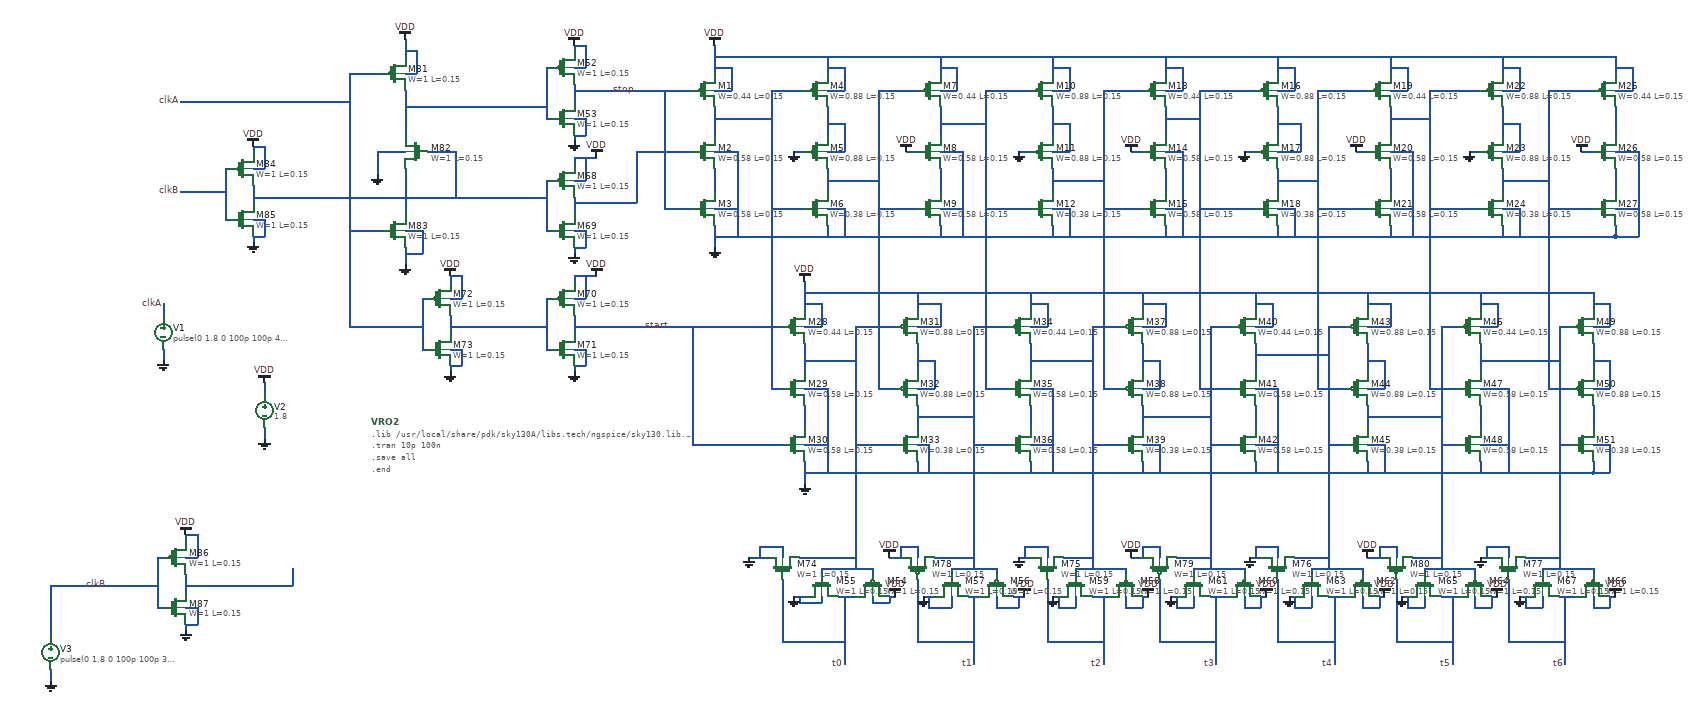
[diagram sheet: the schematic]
v {xschem version=3.4.6 file_version=1.2}
G {}
K {}
V {}
S {}
E {}
N -170 -50 -170 -20 {lab=stop}
N -170 -120 -170 -110 {lab=VDD}
N -170 40 -170 50 {lab=GND}
N -220 -80 -210 -80 {lab=#net1}
N -220 -80 -220 10 {lab=#net1}
N -220 10 -200 10 {lab=#net1}
N 300 860 330 860 {lab=t0}
N 390 860 400 860 {lab=VDD}
N 360 810 360 820 {lab=#net2}
N 270 810 360 810 {lab=#net2}
N 270 810 270 830 {lab=#net2}
N 750 860 780 860 {lab=t2}
N 840 860 850 860 {lab=VDD}
N 680 860 690 860 {lab=GND}
N 810 810 810 820 {lab=#net3}
N 720 810 810 810 {lab=#net3}
N 720 810 720 830 {lab=#net3}
N 960 860 990 860 {lab=t3}
N 1050 860 1060 860 {lab=VDD}
N 890 860 900 860 {lab=GND}
N 1020 810 1020 820 {lab=#net4}
N 930 810 1020 810 {lab=#net4}
N 930 810 930 830 {lab=#net4}
N 1170 860 1200 860 {lab=t4}
N 1260 860 1270 860 {lab=VDD}
N 1100 860 1110 860 {lab=GND}
N 1230 810 1230 820 {lab=#net5}
N 1140 810 1230 810 {lab=#net5}
N 1140 810 1140 830 {lab=#net5}
N 1370 860 1400 860 {lab=t5}
N 1460 860 1470 860 {lab=VDD}
N 1430 810 1430 820 {lab=#net6}
N 1340 810 1430 810 {lab=#net6}
N 1340 810 1340 830 {lab=#net6}
N 1580 860 1610 860 {lab=t6}
N 1670 860 1680 860 {lab=VDD}
N 1510 860 1520 860 {lab=GND}
N 1640 810 1640 820 {lab=#net7}
N 1550 810 1640 810 {lab=#net7}
N 1550 810 1550 830 {lab=#net7}
N -170 150 -170 180 {lab=#net8}
N -170 240 -170 250 {lab=GND}
N -220 120 -210 120 {lab=#net9}
N -220 120 -220 210 {lab=#net9}
N -220 210 -200 210 {lab=#net9}
N -170 360 -170 390 {lab=start}
N -170 450 -170 460 {lab=GND}
N -220 330 -210 330 {lab=#net10}
N -220 330 -220 420 {lab=#net10}
N -220 420 -200 420 {lab=#net10}
N -390 360 -390 390 {lab=#net10}
N -390 290 -390 300 {lab=VDD}
N -390 450 -390 460 {lab=GND}
N -440 330 -430 330 {lab=clkA}
N -440 330 -440 420 {lab=clkA}
N -440 420 -420 420 {lab=clkA}
N -740 130 -740 160 {lab=#net9}
N -740 60 -740 70 {lab=VDD}
N -740 220 -740 230 {lab=GND}
N -790 100 -780 100 {lab=clkB}
N -790 100 -790 190 {lab=clkB}
N -790 190 -770 190 {lab=clkB}
N -170 -40 40 -40 {lab=stop}
N -60 70 40 70 {lab=#net8}
N -60 70 -60 160 {lab=#net8}
N -170 160 -60 160 {lab=#net8}
N -10 170 40 170 {lab=stop}
N -10 -40 -10 170 {lab=stop}
N 80 -120 80 -70 {lab=VDD}
N 80 -10 80 40 {lab=#net11}
N 80 100 80 140 {lab=#net12}
N 80 200 80 240 {lab=GND}
N 280 -100 280 -70 {lab=VDD}
N 280 -10 280 40 {lab=#net13}
N 280 100 280 150 {lab=#net14}
N 280 200 280 220 {lab=GND}
N 480 -100 480 -70 {lab=VDD}
N 480 -10 480 40 {lab=#net15}
N 480 100 480 140 {lab=#net16}
N 480 200 480 220 {lab=GND}
N 680 -100 680 -70 {lab=VDD}
N 680 -10 680 40 {lab=#net17}
N 680 100 680 140 {lab=#net18}
N 680 200 680 220 {lab=GND}
N 880 -100 880 -70 {lab=VDD}
N 880 -10 880 40 {lab=#net19}
N 880 100 880 140 {lab=#net20}
N 880 200 880 220 {lab=GND}
N 1080 -100 1080 -70 {lab=VDD}
N 1080 -10 1080 40 {lab=#net21}
N 1080 100 1080 140 {lab=#net22}
N 1080 200 1080 220 {lab=GND}
N 1280 -100 1280 -70 {lab=VDD}
N 1280 -10 1280 40 {lab=#net23}
N 1280 100 1280 140 {lab=#net24}
N 1280 200 1280 220 {lab=GND}
N 1480 -100 1480 -70 {lab=VDD}
N 1480 -10 1480 40 {lab=#net25}
N 1480 100 1480 140 {lab=#net26}
N 1480 200 1480 220 {lab=GND}
N 1680 -100 1680 -70 {lab=VDD}
N 1680 -10 1680 50 {lab=#net27}
N 1680 100 1680 140 {lab=#net28}
N 1680 200 1680 220 {lab=GND}
N 80 -100 1680 -100 {lab=VDD}
N 80 220 1680 220 {lab=GND}
N -170 380 200 380 {lab=start}
N 40 590 200 590 {lab=start}
N 40 380 40 590 {lab=start}
N 240 300 240 350 {lab=VDD}
N 240 410 240 460 {lab=#net2}
N 240 520 240 560 {lab=#net29}
N 240 620 240 660 {lab=GND}
N 440 320 440 350 {lab=VDD}
N 440 410 440 460 {lab=#net30}
N 440 520 440 570 {lab=#net31}
N 440 620 440 640 {lab=GND}
N 640 320 640 350 {lab=VDD}
N 640 410 640 460 {lab=#net3}
N 640 520 640 560 {lab=#net32}
N 640 620 640 640 {lab=GND}
N 840 320 840 350 {lab=VDD}
N 840 410 840 470 {lab=#net33}
N 840 520 840 560 {lab=#net4}
N 840 620 840 640 {lab=GND}
N 1040 320 1040 350 {lab=VDD}
N 1040 410 1040 460 {lab=#net5}
N 1040 520 1040 570 {lab=#net34}
N 1040 620 1040 640 {lab=GND}
N 1240 320 1240 350 {lab=VDD}
N 1240 410 1240 460 {lab=#net35}
N 1240 520 1240 560 {lab=#net6}
N 1240 620 1240 640 {lab=GND}
N 1440 320 1440 350 {lab=VDD}
N 1440 410 1440 470 {lab=#net7}
N 1440 520 1440 560 {lab=#net36}
N 1440 620 1440 640 {lab=GND}
N 1640 320 1640 350 {lab=VDD}
N 1640 410 1640 470 {lab=#net37}
N 1640 520 1640 570 {lab=#net38}
N 1640 620 1640 640 {lab=GND}
N 240 320 1640 320 {lab=VDD}
N 240 640 1640 640 {lab=GND}
N 180 -40 240 -40 {lab=#net11}
N 180 -40 180 490 {lab=#net11}
N 180 490 200 490 {lab=#net11}
N 370 -40 440 -40 {lab=#net14}
N 370 -40 370 490 {lab=#net14}
N 370 490 400 490 {lab=#net14}
N 560 -40 640 -40 {lab=#net15}
N 560 -40 560 490 {lab=#net15}
N 560 490 600 490 {lab=#net15}
N 940 -40 1040 -40 {lab=#net19}
N 940 -40 940 490 {lab=#net19}
N 940 490 1010 490 {lab=#net19}
N 1150 -40 1240 -40 {lab=#net22}
N 1150 -40 1150 490 {lab=#net22}
N 1150 490 1200 490 {lab=#net22}
N 1350 -40 1440 -40 {lab=#net23}
N 1350 -40 1350 490 {lab=#net23}
N 1350 490 1400 490 {lab=#net23}
N 1560 -40 1640 -40 {lab=#net26}
N 1560 -40 1560 490 {lab=#net26}
N 1560 490 1610 490 {lab=#net26}
N 80 10 180 10 {lab=#net11}
N 180 170 240 170 {lab=#net11}
N 280 120 370 120 {lab=#net14}
N 370 170 440 170 {lab=#net14}
N 480 20 560 20 {lab=#net15}
N 560 170 640 170 {lab=#net15}
N 770 -40 840 -40 {lab=#net18}
N 770 -40 770 490 {lab=#net18}
N 770 490 800 490 {lab=#net18}
N 680 120 770 120 {lab=#net18}
N 770 170 840 170 {lab=#net18}
N 880 10 940 10 {lab=#net19}
N 940 170 1040 170 {lab=#net19}
N 1080 120 1150 120 {lab=#net22}
N 1150 170 1240 170 {lab=#net22}
N 1280 10 1350 10 {lab=#net23}
N 1350 170 1440 170 {lab=#net23}
N 1480 120 1560 120 {lab=#net26}
N 1560 170 1640 170 {lab=#net26}
N 80 -40 110 -40 {lab=VDD}
N 110 -80 110 -40 {lab=VDD}
N 80 -80 110 -80 {lab=VDD}
N 80 70 120 70 {lab=GND}
N 120 70 120 220 {lab=GND}
N 80 170 120 170 {lab=GND}
N 280 -40 310 -40 {lab=VDD}
N 310 -80 310 -40 {lab=VDD}
N 280 -80 310 -80 {lab=VDD}
N 280 70 310 70 {lab=#net13}
N 310 20 310 70 {lab=#net13}
N 280 20 310 20 {lab=#net13}
N 280 170 310 170 {lab=GND}
N 310 170 310 220 {lab=GND}
N 480 -40 510 -40 {lab=VDD}
N 510 -80 510 -40 {lab=VDD}
N 480 -80 510 -80 {lab=VDD}
N 480 70 520 70 {lab=GND}
N 520 70 520 220 {lab=GND}
N 480 170 520 170 {lab=GND}
N 680 -40 710 -40 {lab=VDD}
N 710 -80 710 -40 {lab=VDD}
N 680 -80 710 -80 {lab=VDD}
N 680 70 710 70 {lab=#net17}
N 710 20 710 70 {lab=#net17}
N 680 20 710 20 {lab=#net17}
N 680 170 710 170 {lab=GND}
N 710 170 710 220 {lab=GND}
N 880 -40 910 -40 {lab=VDD}
N 910 -80 910 -40 {lab=VDD}
N 880 -80 910 -80 {lab=VDD}
N 880 70 910 70 {lab=GND}
N 910 70 910 220 {lab=GND}
N 880 170 910 170 {lab=GND}
N 1080 -40 1110 -40 {lab=VDD}
N 1110 -80 1110 -40 {lab=VDD}
N 1080 -80 1110 -80 {lab=VDD}
N 1080 70 1120 70 {lab=#net21}
N 1120 20 1120 70 {lab=#net21}
N 1080 20 1120 20 {lab=#net21}
N 1080 170 1110 170 {lab=GND}
N 1110 170 1110 220 {lab=GND}
N 1280 -40 1310 -40 {lab=VDD}
N 1310 -80 1310 -40 {lab=VDD}
N 1280 -80 1310 -80 {lab=VDD}
N 1280 70 1320 70 {lab=GND}
N 1320 70 1320 220 {lab=GND}
N 1280 170 1320 170 {lab=GND}
N 1480 -40 1510 -40 {lab=VDD}
N 1510 -80 1510 -40 {lab=VDD}
N 1480 -80 1510 -80 {lab=VDD}
N 1480 70 1510 70 {lab=#net25}
N 1510 20 1510 70 {lab=#net25}
N 1480 20 1510 20 {lab=#net25}
N 1480 170 1510 170 {lab=GND}
N 1510 170 1510 220 {lab=GND}
N 1680 -40 1710 -40 {lab=VDD}
N 1710 -80 1710 -40 {lab=VDD}
N 1680 -80 1710 -80 {lab=VDD}
N 1680 70 1720 70 {lab=GND}
N 1720 70 1720 220 {lab=GND}
N 1680 220 1720 220 {lab=GND}
N 1680 170 1720 170 {lab=GND}
N 220 70 240 70 {lab=GND}
N 420 70 440 70 {lab=VDD}
N 620 70 640 70 {lab=GND}
N 820 70 840 70 {lab=VDD}
N 1020 70 1040 70 {lab=GND}
N 1220 70 1240 70 {lab=VDD}
N 1420 70 1440 70 {lab=GND}
N 1620 70 1640 70 {lab=VDD}
N 330 380 400 380 {lab=#net2}
N 330 380 330 810 {lab=#net2}
N 240 440 330 440 {lab=#net2}
N 330 590 400 590 {lab=#net2}
N 750 380 800 380 {lab=#net3}
N 750 380 750 810 {lab=#net3}
N 640 440 750 440 {lab=#net3}
N 750 590 800 590 {lab=#net3}
N 540 380 600 380 {lab=#net31}
N 540 380 540 810 {lab=#net31}
N 440 540 540 540 {lab=#net31}
N 540 590 600 590 {lab=#net31}
N 960 380 1000 380 {lab=#net4}
N 960 380 960 810 {lab=#net4}
N 840 540 960 540 {lab=#net4}
N 960 590 1000 590 {lab=#net4}
N 1170 380 1200 380 {lab=#net5}
N 1170 380 1170 810 {lab=#net5}
N 1040 430 1170 430 {lab=#net5}
N 1170 590 1200 590 {lab=#net5}
N 1370 380 1400 380 {lab=#net6}
N 1370 380 1370 810 {lab=#net6}
N 1370 590 1400 590 {lab=#net6}
N 1240 540 1370 540 {lab=#net6}
N 1580 380 1600 380 {lab=#net7}
N 1580 380 1580 810 {lab=#net7}
N 1440 440 1580 440 {lab=#net7}
N 1580 590 1600 590 {lab=#net7}
N 1640 590 1670 590 {lab=GND}
N 1670 590 1670 640 {lab=GND}
N 1640 640 1670 640 {lab=GND}
N 1640 380 1670 380 {lab=VDD}
N 1670 340 1670 380 {lab=VDD}
N 1640 340 1670 340 {lab=VDD}
N 1640 490 1670 490 {lab=#net37}
N 1670 440 1670 490 {lab=#net37}
N 1640 440 1670 440 {lab=#net37}
N 1440 380 1470 380 {lab=VDD}
N 1470 340 1470 380 {lab=VDD}
N 1440 340 1470 340 {lab=VDD}
N 1440 490 1490 490 {lab=GND}
N 1490 490 1490 640 {lab=GND}
N 1440 590 1490 590 {lab=GND}
N 1240 380 1280 380 {lab=VDD}
N 1280 340 1280 380 {lab=VDD}
N 1240 340 1280 340 {lab=VDD}
N 1240 490 1270 490 {lab=#net35}
N 1270 440 1270 490 {lab=#net35}
N 1240 440 1270 440 {lab=#net35}
N 1240 590 1270 590 {lab=GND}
N 1270 590 1270 640 {lab=GND}
N 1040 380 1070 380 {lab=VDD}
N 1070 340 1070 380 {lab=VDD}
N 1040 340 1070 340 {lab=VDD}
N 1040 490 1080 490 {lab=GND}
N 1080 490 1080 640 {lab=GND}
N 1040 590 1080 590 {lab=GND}
N 840 380 880 380 {lab=VDD}
N 880 340 880 380 {lab=VDD}
N 840 340 880 340 {lab=VDD}
N 840 490 870 490 {lab=#net33}
N 870 440 870 490 {lab=#net33}
N 840 440 870 440 {lab=#net33}
N 840 590 870 590 {lab=GND}
N 870 590 870 640 {lab=GND}
N 640 380 670 380 {lab=VDD}
N 670 340 670 380 {lab=VDD}
N 640 340 670 340 {lab=VDD}
N 640 490 680 490 {lab=GND}
N 680 490 680 640 {lab=GND}
N 640 590 680 590 {lab=GND}
N 440 380 480 380 {lab=VDD}
N 480 340 480 380 {lab=VDD}
N 440 340 480 340 {lab=VDD}
N 440 490 470 490 {lab=#net30}
N 470 440 470 490 {lab=#net30}
N 440 440 470 440 {lab=#net30}
N 440 590 460 590 {lab=GND}
N 460 590 460 640 {lab=GND}
N 240 380 270 380 {lab=VDD}
N 270 340 270 380 {lab=VDD}
N 240 340 270 340 {lab=VDD}
N 240 490 280 490 {lab=GND}
N 280 490 280 640 {lab=GND}
N 240 590 280 590 {lab=GND}
N 230 790 330 790 {lab=#net2}
N 470 790 540 790 {lab=#net31}
N 700 790 750 790 {lab=#net3}
N 900 790 960 790 {lab=#net4}
N 1110 790 1170 790 {lab=#net5}
N 1320 790 1370 790 {lab=#net6}
N 1520 790 1580 790 {lab=#net7}
N 140 790 170 790 {lab=GND}
N 390 790 410 790 {lab=VDD}
N 620 790 640 790 {lab=GND}
N 820 790 840 790 {lab=VDD}
N 1030 790 1050 790 {lab=GND}
N 1240 790 1260 790 {lab=VDD}
N 1440 790 1460 790 {lab=GND}
N 1300 860 1310 860 {lab=GND}
N 310 860 310 980 {lab=t0}
N 540 860 540 980 {lab=t1}
N 770 860 770 980 {lab=t2}
N 970 860 970 980 {lab=t3}
N 1180 860 1180 980 {lab=t4}
N 1390 860 1390 980 {lab=t5}
N 1590 860 1590 980 {lab=t6}
N 200 830 200 940 {lab=t0}
N 200 940 310 940 {lab=t0}
N 440 830 440 940 {lab=t1}
N 440 940 540 940 {lab=t1}
N 670 830 670 940 {lab=t2}
N 670 940 770 940 {lab=t2}
N 870 830 870 940 {lab=t3}
N 870 940 970 940 {lab=t3}
N 1080 830 1080 940 {lab=t4}
N 1080 940 1180 940 {lab=t4}
N 1290 830 1290 940 {lab=t5}
N 1290 940 1390 940 {lab=t5}
N 1490 830 1490 940 {lab=t6}
N 1490 940 1590 940 {lab=t6}
N -570 -70 -510 -70 {lab=clkA}
N -570 -70 -570 380 {lab=clkA}
N -570 380 -440 380 {lab=clkA}
N -570 210 -510 210 {lab=clkA}
N -470 240 -470 270 {lab=GND}
N -470 210 -440 210 {lab=GND}
N -440 210 -440 250 {lab=GND}
N -470 250 -440 250 {lab=GND}
N -470 100 -470 180 {lab=#net39}
N -520 70 -470 70 {lab=GND}
N -520 70 -520 110 {lab=GND}
N -740 150 -220 150 {lab=#net9}
N -430 70 -380 70 {lab=#net9}
N -380 70 -380 150 {lab=#net9}
N -470 -40 -470 40 {lab=#net1}
N -470 -10 -220 -10 {lab=#net1}
N -390 380 -220 380 {lab=#net10}
N -470 -130 -470 -100 {lab=VDD}
N -470 -70 -450 -70 {lab=VDD}
N -450 -110 -450 -70 {lab=VDD}
N -470 -110 -450 -110 {lab=VDD}
N 270 860 270 870 {lab=GND}
N 230 870 270 870 {lab=GND}
N 230 860 230 870 {lab=GND}
N 220 860 240 860 {lab=GND}
N 360 860 360 870 {lab=VDD}
N 360 870 390 870 {lab=VDD}
N 390 860 390 870 {lab=VDD}
N 720 860 720 880 {lab=GND}
N 690 880 720 880 {lab=GND}
N 690 860 690 880 {lab=GND}
N 810 860 810 880 {lab=VDD}
N 810 880 840 880 {lab=VDD}
N 840 860 840 880 {lab=VDD}
N 930 860 930 880 {lab=GND}
N 900 880 930 880 {lab=GND}
N 900 860 900 880 {lab=GND}
N 1020 860 1020 880 {lab=VDD}
N 1020 880 1050 880 {lab=VDD}
N 1050 860 1050 880 {lab=VDD}
N 1140 860 1140 880 {lab=GND}
N 1110 880 1140 880 {lab=GND}
N 1110 860 1110 880 {lab=GND}
N 1230 860 1230 880 {lab=VDD}
N 1230 880 1260 880 {lab=VDD}
N 1260 860 1260 880 {lab=VDD}
N 1340 860 1340 880 {lab=GND}
N 1310 880 1340 880 {lab=GND}
N 1310 860 1310 880 {lab=GND}
N 1430 860 1430 880 {lab=VDD}
N 1430 880 1460 880 {lab=VDD}
N 1460 860 1460 880 {lab=VDD}
N 1550 860 1550 880 {lab=GND}
N 1520 880 1550 880 {lab=GND}
N 1520 860 1520 880 {lab=GND}
N 1640 860 1640 880 {lab=VDD}
N 1640 880 1670 880 {lab=VDD}
N 1670 860 1670 880 {lab=VDD}
N -170 -80 -150 -80 {lab=VDD}
N -150 -120 -150 -80 {lab=VDD}
N -170 -120 -150 -120 {lab=VDD}
N -170 10 -150 10 {lab=GND}
N -150 10 -150 40 {lab=GND}
N -170 40 -150 40 {lab=GND}
N -170 80 -170 90 {lab=VDD}
N -170 80 -130 80 {lab=VDD}
N -170 120 -150 120 {lab=VDD}
N -150 80 -150 120 {lab=VDD}
N -170 210 -150 210 {lab=GND}
N -150 210 -150 240 {lab=GND}
N -170 240 -150 240 {lab=GND}
N -170 290 -170 300 {lab=VDD}
N -170 290 -130 290 {lab=VDD}
N -170 330 -150 330 {lab=VDD}
N -150 290 -150 330 {lab=VDD}
N -170 420 -150 420 {lab=GND}
N -150 420 -150 450 {lab=GND}
N -170 450 -150 450 {lab=GND}
N -390 420 -370 420 {lab=GND}
N -370 420 -370 450 {lab=GND}
N -390 450 -370 450 {lab=GND}
N -390 330 -370 330 {lab=VDD}
N -370 290 -370 330 {lab=VDD}
N -390 290 -370 290 {lab=VDD}
N -740 100 -720 100 {lab=VDD}
N -720 60 -720 100 {lab=VDD}
N -740 60 -720 60 {lab=VDD}
N -740 190 -720 190 {lab=GND}
N -720 190 -720 220 {lab=GND}
N -740 220 -720 220 {lab=GND}
N -870 140 -790 140 {lab=clkB}
N -870 -20 -570 -20 {lab=clkA}
N -900 340 -900 360 {lab=clkA}
N -900 420 -900 440 {lab=GND}
N -720 480 -720 500 {lab=VDD}
N -720 560 -720 580 {lab=GND}
N -1100 910 -1100 930 {lab=clkB}
N -1100 990 -1100 1010 {lab=GND}
N 200 770 200 790 {lab=GND}
N 160 770 200 770 {lab=GND}
N 160 770 160 790 {lab=GND}
N 440 770 440 790 {lab=VDD}
N 410 770 440 770 {lab=VDD}
N 410 770 410 790 {lab=VDD}
N 670 770 670 790 {lab=GND}
N 630 770 670 770 {lab=GND}
N 630 770 630 790 {lab=GND}
N 870 770 870 790 {lab=VDD}
N 840 770 870 770 {lab=VDD}
N 840 770 840 790 {lab=VDD}
N 1080 770 1080 790 {lab=GND}
N 1040 770 1080 770 {lab=GND}
N 1040 770 1040 790 {lab=GND}
N 1290 770 1290 790 {lab=VDD}
N 1260 770 1290 770 {lab=VDD}
N 1260 770 1260 790 {lab=VDD}
N 1490 770 1490 790 {lab=GND}
N 1450 770 1490 770 {lab=GND}
N 1450 770 1450 790 {lab=GND}
N 500 810 580 810 {lab=#net31}
N 580 810 580 830 {lab=#net31}
N 610 860 630 860 {lab=VDD}
N 580 860 580 880 {lab=VDD}
N 580 880 620 880 {lab=VDD}
N 620 860 620 880 {lab=VDD}
N 530 860 550 860 {lab=t1}
N 500 810 500 820 {lab=#net31}
N 450 860 470 860 {lab=GND}
N 500 860 500 880 {lab=GND}
N 460 880 500 880 {lab=GND}
N 460 860 460 880 {lab=GND}
N -860 820 -860 850 {lab=#net40}
N -860 750 -860 760 {lab=VDD}
N -860 910 -860 920 {lab=GND}
N -910 790 -900 790 {lab=clkB}
N -910 790 -910 880 {lab=clkB}
N -910 880 -890 880 {lab=clkB}
N -1040 840 -910 840 {lab=clkB}
N -860 840 -690 840 {lab=#net40}
N -860 880 -840 880 {lab=GND}
N -840 880 -840 910 {lab=GND}
N -860 910 -840 910 {lab=GND}
N -860 790 -840 790 {lab=VDD}
N -840 750 -840 790 {lab=VDD}
N -860 750 -840 750 {lab=VDD}
N -1100 840 -1100 910 {lab=clkB}
N -1100 840 -1040 840 {lab=clkB}
N -690 840 -670 840 {lab=#net40}
N -670 810 -670 840 {lab=#net40}
C {/usr/local/share/pdk/sky130A/libs.tech/xschem/sky130_fd_pr/pfet_01v8.sym} 60 -40 0 0 {name=M1
W=0.44
L=0.15
nf=1
mult=1
ad="'int((nf+1)/2) * W/nf * 0.29'" 
pd="'2*int((nf+1)/2) * (W/nf + 0.29)'"
as="'int((nf+2)/2) * W/nf * 0.29'" 
ps="'2*int((nf+2)/2) * (W/nf + 0.29)'"
nrd="'0.29 / W'" nrs="'0.29 / W'"
sa=0 sb=0 sd=0
model=pfet_01v8
spiceprefix=X
}
C {/usr/local/share/pdk/sky130A/libs.tech/xschem/sky130_fd_pr/nfet_01v8.sym} 60 70 0 0 {name=M2
W=0.58
L=0.15
nf=1 
mult=1
ad="'int((nf+1)/2) * W/nf * 0.29'" 
pd="'2*int((nf+1)/2) * (W/nf + 0.29)'"
as="'int((nf+2)/2) * W/nf * 0.29'" 
ps="'2*int((nf+2)/2) * (W/nf + 0.29)'"
nrd="'0.29 / W'" nrs="'0.29 / W'"
sa=0 sb=0 sd=0
model=nfet_01v8
spiceprefix=X
}
C {/usr/local/share/pdk/sky130A/libs.tech/xschem/sky130_fd_pr/nfet_01v8.sym} 60 170 0 0 {name=M3
W=0.58
L=0.15
nf=1 
mult=1
ad="'int((nf+1)/2) * W/nf * 0.29'" 
pd="'2*int((nf+1)/2) * (W/nf + 0.29)'"
as="'int((nf+2)/2) * W/nf * 0.29'" 
ps="'2*int((nf+2)/2) * (W/nf + 0.29)'"
nrd="'0.29 / W'" nrs="'0.29 / W'"
sa=0 sb=0 sd=0
model=nfet_01v8
spiceprefix=X
}
C {/usr/local/share/pdk/sky130A/libs.tech/xschem/sky130_fd_pr/pfet_01v8.sym} 260 -40 0 0 {name=M4
W=0.88
L=0.15
nf=1
mult=1
ad="'int((nf+1)/2) * W/nf * 0.29'" 
pd="'2*int((nf+1)/2) * (W/nf + 0.29)'"
as="'int((nf+2)/2) * W/nf * 0.29'" 
ps="'2*int((nf+2)/2) * (W/nf + 0.29)'"
nrd="'0.29 / W'" nrs="'0.29 / W'"
sa=0 sb=0 sd=0
model=pfet_01v8
spiceprefix=X
}
C {/usr/local/share/pdk/sky130A/libs.tech/xschem/sky130_fd_pr/pfet_01v8.sym} 260 70 0 0 {name=M5
W=0.88
L=0.15
nf=1
mult=1
ad="'int((nf+1)/2) * W/nf * 0.29'" 
pd="'2*int((nf+1)/2) * (W/nf + 0.29)'"
as="'int((nf+2)/2) * W/nf * 0.29'" 
ps="'2*int((nf+2)/2) * (W/nf + 0.29)'"
nrd="'0.29 / W'" nrs="'0.29 / W'"
sa=0 sb=0 sd=0
model=pfet_01v8
spiceprefix=X
}
C {/usr/local/share/pdk/sky130A/libs.tech/xschem/sky130_fd_pr/nfet_01v8.sym} 260 170 0 0 {name=M6
W=0.38
L=0.15
nf=1 
mult=1
ad="'int((nf+1)/2) * W/nf * 0.29'" 
pd="'2*int((nf+1)/2) * (W/nf + 0.29)'"
as="'int((nf+2)/2) * W/nf * 0.29'" 
ps="'2*int((nf+2)/2) * (W/nf + 0.29)'"
nrd="'0.29 / W'" nrs="'0.29 / W'"
sa=0 sb=0 sd=0
model=nfet_01v8
spiceprefix=X
}
C {/usr/local/share/pdk/sky130A/libs.tech/xschem/sky130_fd_pr/pfet_01v8.sym} 460 -40 0 0 {name=M7
W=0.44
L=0.15
nf=1
mult=1
ad="'int((nf+1)/2) * W/nf * 0.29'" 
pd="'2*int((nf+1)/2) * (W/nf + 0.29)'"
as="'int((nf+2)/2) * W/nf * 0.29'" 
ps="'2*int((nf+2)/2) * (W/nf + 0.29)'"
nrd="'0.29 / W'" nrs="'0.29 / W'"
sa=0 sb=0 sd=0
model=pfet_01v8
spiceprefix=X
}
C {/usr/local/share/pdk/sky130A/libs.tech/xschem/sky130_fd_pr/nfet_01v8.sym} 460 70 0 0 {name=M8
W=0.58
L=0.15
nf=1 
mult=1
ad="'int((nf+1)/2) * W/nf * 0.29'" 
pd="'2*int((nf+1)/2) * (W/nf + 0.29)'"
as="'int((nf+2)/2) * W/nf * 0.29'" 
ps="'2*int((nf+2)/2) * (W/nf + 0.29)'"
nrd="'0.29 / W'" nrs="'0.29 / W'"
sa=0 sb=0 sd=0
model=nfet_01v8
spiceprefix=X
}
C {/usr/local/share/pdk/sky130A/libs.tech/xschem/sky130_fd_pr/nfet_01v8.sym} 460 170 0 0 {name=M9
W=0.58
L=0.15
nf=1 
mult=1
ad="'int((nf+1)/2) * W/nf * 0.29'" 
pd="'2*int((nf+1)/2) * (W/nf + 0.29)'"
as="'int((nf+2)/2) * W/nf * 0.29'" 
ps="'2*int((nf+2)/2) * (W/nf + 0.29)'"
nrd="'0.29 / W'" nrs="'0.29 / W'"
sa=0 sb=0 sd=0
model=nfet_01v8
spiceprefix=X
}
C {/usr/local/share/pdk/sky130A/libs.tech/xschem/sky130_fd_pr/pfet_01v8.sym} 660 -40 0 0 {name=M10
W=0.88
L=0.15
nf=1
mult=1
ad="'int((nf+1)/2) * W/nf * 0.29'" 
pd="'2*int((nf+1)/2) * (W/nf + 0.29)'"
as="'int((nf+2)/2) * W/nf * 0.29'" 
ps="'2*int((nf+2)/2) * (W/nf + 0.29)'"
nrd="'0.29 / W'" nrs="'0.29 / W'"
sa=0 sb=0 sd=0
model=pfet_01v8
spiceprefix=X
}
C {/usr/local/share/pdk/sky130A/libs.tech/xschem/sky130_fd_pr/pfet_01v8.sym} 660 70 0 0 {name=M11
W=0.88
L=0.15
nf=1
mult=1
ad="'int((nf+1)/2) * W/nf * 0.29'" 
pd="'2*int((nf+1)/2) * (W/nf + 0.29)'"
as="'int((nf+2)/2) * W/nf * 0.29'" 
ps="'2*int((nf+2)/2) * (W/nf + 0.29)'"
nrd="'0.29 / W'" nrs="'0.29 / W'"
sa=0 sb=0 sd=0
model=pfet_01v8
spiceprefix=X
}
C {/usr/local/share/pdk/sky130A/libs.tech/xschem/sky130_fd_pr/nfet_01v8.sym} 660 170 0 0 {name=M12
W=0.38
L=0.15
nf=1 
mult=1
ad="'int((nf+1)/2) * W/nf * 0.29'" 
pd="'2*int((nf+1)/2) * (W/nf + 0.29)'"
as="'int((nf+2)/2) * W/nf * 0.29'" 
ps="'2*int((nf+2)/2) * (W/nf + 0.29)'"
nrd="'0.29 / W'" nrs="'0.29 / W'"
sa=0 sb=0 sd=0
model=nfet_01v8
spiceprefix=X
}
C {/usr/local/share/pdk/sky130A/libs.tech/xschem/sky130_fd_pr/pfet_01v8.sym} 860 -40 0 0 {name=M13
W=0.44
L=0.15
nf=1
mult=1
ad="'int((nf+1)/2) * W/nf * 0.29'" 
pd="'2*int((nf+1)/2) * (W/nf + 0.29)'"
as="'int((nf+2)/2) * W/nf * 0.29'" 
ps="'2*int((nf+2)/2) * (W/nf + 0.29)'"
nrd="'0.29 / W'" nrs="'0.29 / W'"
sa=0 sb=0 sd=0
model=pfet_01v8
spiceprefix=X
}
C {/usr/local/share/pdk/sky130A/libs.tech/xschem/sky130_fd_pr/nfet_01v8.sym} 860 70 0 0 {name=M14
W=0.58
L=0.15
nf=1 
mult=1
ad="'int((nf+1)/2) * W/nf * 0.29'" 
pd="'2*int((nf+1)/2) * (W/nf + 0.29)'"
as="'int((nf+2)/2) * W/nf * 0.29'" 
ps="'2*int((nf+2)/2) * (W/nf + 0.29)'"
nrd="'0.29 / W'" nrs="'0.29 / W'"
sa=0 sb=0 sd=0
model=nfet_01v8
spiceprefix=X
}
C {/usr/local/share/pdk/sky130A/libs.tech/xschem/sky130_fd_pr/nfet_01v8.sym} 860 170 0 0 {name=M15
W=0.58
L=0.15
nf=1 
mult=1
ad="'int((nf+1)/2) * W/nf * 0.29'" 
pd="'2*int((nf+1)/2) * (W/nf + 0.29)'"
as="'int((nf+2)/2) * W/nf * 0.29'" 
ps="'2*int((nf+2)/2) * (W/nf + 0.29)'"
nrd="'0.29 / W'" nrs="'0.29 / W'"
sa=0 sb=0 sd=0
model=nfet_01v8
spiceprefix=X
}
C {/usr/local/share/pdk/sky130A/libs.tech/xschem/sky130_fd_pr/pfet_01v8.sym} 1060 -40 0 0 {name=M16
W=0.88
L=0.15
nf=1
mult=1
ad="'int((nf+1)/2) * W/nf * 0.29'" 
pd="'2*int((nf+1)/2) * (W/nf + 0.29)'"
as="'int((nf+2)/2) * W/nf * 0.29'" 
ps="'2*int((nf+2)/2) * (W/nf + 0.29)'"
nrd="'0.29 / W'" nrs="'0.29 / W'"
sa=0 sb=0 sd=0
model=pfet_01v8
spiceprefix=X
}
C {/usr/local/share/pdk/sky130A/libs.tech/xschem/sky130_fd_pr/pfet_01v8.sym} 1060 70 0 0 {name=M17
W=0.88
L=0.15
nf=1
mult=1
ad="'int((nf+1)/2) * W/nf * 0.29'" 
pd="'2*int((nf+1)/2) * (W/nf + 0.29)'"
as="'int((nf+2)/2) * W/nf * 0.29'" 
ps="'2*int((nf+2)/2) * (W/nf + 0.29)'"
nrd="'0.29 / W'" nrs="'0.29 / W'"
sa=0 sb=0 sd=0
model=pfet_01v8
spiceprefix=X
}
C {/usr/local/share/pdk/sky130A/libs.tech/xschem/sky130_fd_pr/nfet_01v8.sym} 1060 170 0 0 {name=M18
W=0.38
L=0.15
nf=1 
mult=1
ad="'int((nf+1)/2) * W/nf * 0.29'" 
pd="'2*int((nf+1)/2) * (W/nf + 0.29)'"
as="'int((nf+2)/2) * W/nf * 0.29'" 
ps="'2*int((nf+2)/2) * (W/nf + 0.29)'"
nrd="'0.29 / W'" nrs="'0.29 / W'"
sa=0 sb=0 sd=0
model=nfet_01v8
spiceprefix=X
}
C {/usr/local/share/pdk/sky130A/libs.tech/xschem/sky130_fd_pr/pfet_01v8.sym} 1260 -40 0 0 {name=M19
W=0.44
L=0.15
nf=1
mult=1
ad="'int((nf+1)/2) * W/nf * 0.29'" 
pd="'2*int((nf+1)/2) * (W/nf + 0.29)'"
as="'int((nf+2)/2) * W/nf * 0.29'" 
ps="'2*int((nf+2)/2) * (W/nf + 0.29)'"
nrd="'0.29 / W'" nrs="'0.29 / W'"
sa=0 sb=0 sd=0
model=pfet_01v8
spiceprefix=X
}
C {/usr/local/share/pdk/sky130A/libs.tech/xschem/sky130_fd_pr/nfet_01v8.sym} 1260 70 0 0 {name=M20
W=0.58
L=0.15
nf=1 
mult=1
ad="'int((nf+1)/2) * W/nf * 0.29'" 
pd="'2*int((nf+1)/2) * (W/nf + 0.29)'"
as="'int((nf+2)/2) * W/nf * 0.29'" 
ps="'2*int((nf+2)/2) * (W/nf + 0.29)'"
nrd="'0.29 / W'" nrs="'0.29 / W'"
sa=0 sb=0 sd=0
model=nfet_01v8
spiceprefix=X
}
C {/usr/local/share/pdk/sky130A/libs.tech/xschem/sky130_fd_pr/nfet_01v8.sym} 1260 170 0 0 {name=M21
W=0.58
L=0.15
nf=1 
mult=1
ad="'int((nf+1)/2) * W/nf * 0.29'" 
pd="'2*int((nf+1)/2) * (W/nf + 0.29)'"
as="'int((nf+2)/2) * W/nf * 0.29'" 
ps="'2*int((nf+2)/2) * (W/nf + 0.29)'"
nrd="'0.29 / W'" nrs="'0.29 / W'"
sa=0 sb=0 sd=0
model=nfet_01v8
spiceprefix=X
}
C {/usr/local/share/pdk/sky130A/libs.tech/xschem/sky130_fd_pr/pfet_01v8.sym} 1460 -40 0 0 {name=M22
W=0.88
L=0.15
nf=1
mult=1
ad="'int((nf+1)/2) * W/nf * 0.29'" 
pd="'2*int((nf+1)/2) * (W/nf + 0.29)'"
as="'int((nf+2)/2) * W/nf * 0.29'" 
ps="'2*int((nf+2)/2) * (W/nf + 0.29)'"
nrd="'0.29 / W'" nrs="'0.29 / W'"
sa=0 sb=0 sd=0
model=pfet_01v8
spiceprefix=X
}
C {/usr/local/share/pdk/sky130A/libs.tech/xschem/sky130_fd_pr/pfet_01v8.sym} 1460 70 0 0 {name=M23
W=0.88
L=0.15
nf=1
mult=1
ad="'int((nf+1)/2) * W/nf * 0.29'" 
pd="'2*int((nf+1)/2) * (W/nf + 0.29)'"
as="'int((nf+2)/2) * W/nf * 0.29'" 
ps="'2*int((nf+2)/2) * (W/nf + 0.29)'"
nrd="'0.29 / W'" nrs="'0.29 / W'"
sa=0 sb=0 sd=0
model=pfet_01v8
spiceprefix=X
}
C {/usr/local/share/pdk/sky130A/libs.tech/xschem/sky130_fd_pr/nfet_01v8.sym} 1460 170 0 0 {name=M24
W=0.38
L=0.15
nf=1 
mult=1
ad="'int((nf+1)/2) * W/nf * 0.29'" 
pd="'2*int((nf+1)/2) * (W/nf + 0.29)'"
as="'int((nf+2)/2) * W/nf * 0.29'" 
ps="'2*int((nf+2)/2) * (W/nf + 0.29)'"
nrd="'0.29 / W'" nrs="'0.29 / W'"
sa=0 sb=0 sd=0
model=nfet_01v8
spiceprefix=X
}
C {/usr/local/share/pdk/sky130A/libs.tech/xschem/sky130_fd_pr/pfet_01v8.sym} 1660 -40 0 0 {name=M25
W=0.44
L=0.15
nf=1
mult=1
ad="'int((nf+1)/2) * W/nf * 0.29'" 
pd="'2*int((nf+1)/2) * (W/nf + 0.29)'"
as="'int((nf+2)/2) * W/nf * 0.29'" 
ps="'2*int((nf+2)/2) * (W/nf + 0.29)'"
nrd="'0.29 / W'" nrs="'0.29 / W'"
sa=0 sb=0 sd=0
model=pfet_01v8
spiceprefix=X
}
C {/usr/local/share/pdk/sky130A/libs.tech/xschem/sky130_fd_pr/nfet_01v8.sym} 1660 70 0 0 {name=M26
W=0.58
L=0.15
nf=1 
mult=1
ad="'int((nf+1)/2) * W/nf * 0.29'" 
pd="'2*int((nf+1)/2) * (W/nf + 0.29)'"
as="'int((nf+2)/2) * W/nf * 0.29'" 
ps="'2*int((nf+2)/2) * (W/nf + 0.29)'"
nrd="'0.29 / W'" nrs="'0.29 / W'"
sa=0 sb=0 sd=0
model=nfet_01v8
spiceprefix=X
}
C {/usr/local/share/pdk/sky130A/libs.tech/xschem/sky130_fd_pr/nfet_01v8.sym} 1660 170 0 0 {name=M27
W=0.58
L=0.15
nf=1 
mult=1
ad="'int((nf+1)/2) * W/nf * 0.29'" 
pd="'2*int((nf+1)/2) * (W/nf + 0.29)'"
as="'int((nf+2)/2) * W/nf * 0.29'" 
ps="'2*int((nf+2)/2) * (W/nf + 0.29)'"
nrd="'0.29 / W'" nrs="'0.29 / W'"
sa=0 sb=0 sd=0
model=nfet_01v8
spiceprefix=X
}
C {/usr/local/share/pdk/sky130A/libs.tech/xschem/sky130_fd_pr/pfet_01v8.sym} 220 380 0 0 {name=M28
W=0.44
L=0.15
nf=1
mult=1
ad="'int((nf+1)/2) * W/nf * 0.29'" 
pd="'2*int((nf+1)/2) * (W/nf + 0.29)'"
as="'int((nf+2)/2) * W/nf * 0.29'" 
ps="'2*int((nf+2)/2) * (W/nf + 0.29)'"
nrd="'0.29 / W'" nrs="'0.29 / W'"
sa=0 sb=0 sd=0
model=pfet_01v8
spiceprefix=X
}
C {/usr/local/share/pdk/sky130A/libs.tech/xschem/sky130_fd_pr/nfet_01v8.sym} 220 490 0 0 {name=M29
W=0.58
L=0.15
nf=1 
mult=1
ad="'int((nf+1)/2) * W/nf * 0.29'" 
pd="'2*int((nf+1)/2) * (W/nf + 0.29)'"
as="'int((nf+2)/2) * W/nf * 0.29'" 
ps="'2*int((nf+2)/2) * (W/nf + 0.29)'"
nrd="'0.29 / W'" nrs="'0.29 / W'"
sa=0 sb=0 sd=0
model=nfet_01v8
spiceprefix=X
}
C {/usr/local/share/pdk/sky130A/libs.tech/xschem/sky130_fd_pr/nfet_01v8.sym} 220 590 0 0 {name=M30
W=0.58
L=0.15
nf=1 
mult=1
ad="'int((nf+1)/2) * W/nf * 0.29'" 
pd="'2*int((nf+1)/2) * (W/nf + 0.29)'"
as="'int((nf+2)/2) * W/nf * 0.29'" 
ps="'2*int((nf+2)/2) * (W/nf + 0.29)'"
nrd="'0.29 / W'" nrs="'0.29 / W'"
sa=0 sb=0 sd=0
model=nfet_01v8
spiceprefix=X
}
C {/usr/local/share/pdk/sky130A/libs.tech/xschem/sky130_fd_pr/pfet_01v8.sym} 420 380 0 0 {name=M31
W=0.88
L=0.15
nf=1
mult=1
ad="'int((nf+1)/2) * W/nf * 0.29'" 
pd="'2*int((nf+1)/2) * (W/nf + 0.29)'"
as="'int((nf+2)/2) * W/nf * 0.29'" 
ps="'2*int((nf+2)/2) * (W/nf + 0.29)'"
nrd="'0.29 / W'" nrs="'0.29 / W'"
sa=0 sb=0 sd=0
model=pfet_01v8
spiceprefix=X
}
C {/usr/local/share/pdk/sky130A/libs.tech/xschem/sky130_fd_pr/pfet_01v8.sym} 420 490 0 0 {name=M32
W=0.88
L=0.15
nf=1
mult=1
ad="'int((nf+1)/2) * W/nf * 0.29'" 
pd="'2*int((nf+1)/2) * (W/nf + 0.29)'"
as="'int((nf+2)/2) * W/nf * 0.29'" 
ps="'2*int((nf+2)/2) * (W/nf + 0.29)'"
nrd="'0.29 / W'" nrs="'0.29 / W'"
sa=0 sb=0 sd=0
model=pfet_01v8
spiceprefix=X
}
C {/usr/local/share/pdk/sky130A/libs.tech/xschem/sky130_fd_pr/nfet_01v8.sym} 420 590 0 0 {name=M33
W=0.38
L=0.15
nf=1 
mult=1
ad="'int((nf+1)/2) * W/nf * 0.29'" 
pd="'2*int((nf+1)/2) * (W/nf + 0.29)'"
as="'int((nf+2)/2) * W/nf * 0.29'" 
ps="'2*int((nf+2)/2) * (W/nf + 0.29)'"
nrd="'0.29 / W'" nrs="'0.29 / W'"
sa=0 sb=0 sd=0
model=nfet_01v8
spiceprefix=X
}
C {/usr/local/share/pdk/sky130A/libs.tech/xschem/sky130_fd_pr/pfet_01v8.sym} 620 380 0 0 {name=M34
W=0.44
L=0.15
nf=1
mult=1
ad="'int((nf+1)/2) * W/nf * 0.29'" 
pd="'2*int((nf+1)/2) * (W/nf + 0.29)'"
as="'int((nf+2)/2) * W/nf * 0.29'" 
ps="'2*int((nf+2)/2) * (W/nf + 0.29)'"
nrd="'0.29 / W'" nrs="'0.29 / W'"
sa=0 sb=0 sd=0
model=pfet_01v8
spiceprefix=X
}
C {/usr/local/share/pdk/sky130A/libs.tech/xschem/sky130_fd_pr/nfet_01v8.sym} 620 490 0 0 {name=M35
W=0.58
L=0.15
nf=1 
mult=1
ad="'int((nf+1)/2) * W/nf * 0.29'" 
pd="'2*int((nf+1)/2) * (W/nf + 0.29)'"
as="'int((nf+2)/2) * W/nf * 0.29'" 
ps="'2*int((nf+2)/2) * (W/nf + 0.29)'"
nrd="'0.29 / W'" nrs="'0.29 / W'"
sa=0 sb=0 sd=0
model=nfet_01v8
spiceprefix=X
}
C {/usr/local/share/pdk/sky130A/libs.tech/xschem/sky130_fd_pr/nfet_01v8.sym} 620 590 0 0 {name=M36
W=0.58
L=0.15
nf=1 
mult=1
ad="'int((nf+1)/2) * W/nf * 0.29'" 
pd="'2*int((nf+1)/2) * (W/nf + 0.29)'"
as="'int((nf+2)/2) * W/nf * 0.29'" 
ps="'2*int((nf+2)/2) * (W/nf + 0.29)'"
nrd="'0.29 / W'" nrs="'0.29 / W'"
sa=0 sb=0 sd=0
model=nfet_01v8
spiceprefix=X
}
C {/usr/local/share/pdk/sky130A/libs.tech/xschem/sky130_fd_pr/pfet_01v8.sym} 820 380 0 0 {name=M37
W=0.88
L=0.15
nf=1
mult=1
ad="'int((nf+1)/2) * W/nf * 0.29'" 
pd="'2*int((nf+1)/2) * (W/nf + 0.29)'"
as="'int((nf+2)/2) * W/nf * 0.29'" 
ps="'2*int((nf+2)/2) * (W/nf + 0.29)'"
nrd="'0.29 / W'" nrs="'0.29 / W'"
sa=0 sb=0 sd=0
model=pfet_01v8
spiceprefix=X
}
C {/usr/local/share/pdk/sky130A/libs.tech/xschem/sky130_fd_pr/pfet_01v8.sym} 820 490 0 0 {name=M38
W=0.88
L=0.15
nf=1
mult=1
ad="'int((nf+1)/2) * W/nf * 0.29'" 
pd="'2*int((nf+1)/2) * (W/nf + 0.29)'"
as="'int((nf+2)/2) * W/nf * 0.29'" 
ps="'2*int((nf+2)/2) * (W/nf + 0.29)'"
nrd="'0.29 / W'" nrs="'0.29 / W'"
sa=0 sb=0 sd=0
model=pfet_01v8
spiceprefix=X
}
C {/usr/local/share/pdk/sky130A/libs.tech/xschem/sky130_fd_pr/nfet_01v8.sym} 820 590 0 0 {name=M39
W=0.38
L=0.15
nf=1 
mult=1
ad="'int((nf+1)/2) * W/nf * 0.29'" 
pd="'2*int((nf+1)/2) * (W/nf + 0.29)'"
as="'int((nf+2)/2) * W/nf * 0.29'" 
ps="'2*int((nf+2)/2) * (W/nf + 0.29)'"
nrd="'0.29 / W'" nrs="'0.29 / W'"
sa=0 sb=0 sd=0
model=nfet_01v8
spiceprefix=X
}
C {/usr/local/share/pdk/sky130A/libs.tech/xschem/sky130_fd_pr/pfet_01v8.sym} 1020 380 0 0 {name=M40
W=0.44
L=0.15
nf=1
mult=1
ad="'int((nf+1)/2) * W/nf * 0.29'" 
pd="'2*int((nf+1)/2) * (W/nf + 0.29)'"
as="'int((nf+2)/2) * W/nf * 0.29'" 
ps="'2*int((nf+2)/2) * (W/nf + 0.29)'"
nrd="'0.29 / W'" nrs="'0.29 / W'"
sa=0 sb=0 sd=0
model=pfet_01v8
spiceprefix=X
}
C {/usr/local/share/pdk/sky130A/libs.tech/xschem/sky130_fd_pr/nfet_01v8.sym} 1020 490 0 0 {name=M41
W=0.58
L=0.15
nf=1 
mult=1
ad="'int((nf+1)/2) * W/nf * 0.29'" 
pd="'2*int((nf+1)/2) * (W/nf + 0.29)'"
as="'int((nf+2)/2) * W/nf * 0.29'" 
ps="'2*int((nf+2)/2) * (W/nf + 0.29)'"
nrd="'0.29 / W'" nrs="'0.29 / W'"
sa=0 sb=0 sd=0
model=nfet_01v8
spiceprefix=X
}
C {/usr/local/share/pdk/sky130A/libs.tech/xschem/sky130_fd_pr/nfet_01v8.sym} 1020 590 0 0 {name=M42
W=0.58
L=0.15
nf=1 
mult=1
ad="'int((nf+1)/2) * W/nf * 0.29'" 
pd="'2*int((nf+1)/2) * (W/nf + 0.29)'"
as="'int((nf+2)/2) * W/nf * 0.29'" 
ps="'2*int((nf+2)/2) * (W/nf + 0.29)'"
nrd="'0.29 / W'" nrs="'0.29 / W'"
sa=0 sb=0 sd=0
model=nfet_01v8
spiceprefix=X
}
C {/usr/local/share/pdk/sky130A/libs.tech/xschem/sky130_fd_pr/pfet_01v8.sym} 1220 380 0 0 {name=M43
W=0.88
L=0.15
nf=1
mult=1
ad="'int((nf+1)/2) * W/nf * 0.29'" 
pd="'2*int((nf+1)/2) * (W/nf + 0.29)'"
as="'int((nf+2)/2) * W/nf * 0.29'" 
ps="'2*int((nf+2)/2) * (W/nf + 0.29)'"
nrd="'0.29 / W'" nrs="'0.29 / W'"
sa=0 sb=0 sd=0
model=pfet_01v8
spiceprefix=X
}
C {/usr/local/share/pdk/sky130A/libs.tech/xschem/sky130_fd_pr/pfet_01v8.sym} 1220 490 0 0 {name=M44
W=0.88
L=0.15
nf=1
mult=1
ad="'int((nf+1)/2) * W/nf * 0.29'" 
pd="'2*int((nf+1)/2) * (W/nf + 0.29)'"
as="'int((nf+2)/2) * W/nf * 0.29'" 
ps="'2*int((nf+2)/2) * (W/nf + 0.29)'"
nrd="'0.29 / W'" nrs="'0.29 / W'"
sa=0 sb=0 sd=0
model=pfet_01v8
spiceprefix=X
}
C {/usr/local/share/pdk/sky130A/libs.tech/xschem/sky130_fd_pr/nfet_01v8.sym} 1220 590 0 0 {name=M45
W=0.38
L=0.15
nf=1 
mult=1
ad="'int((nf+1)/2) * W/nf * 0.29'" 
pd="'2*int((nf+1)/2) * (W/nf + 0.29)'"
as="'int((nf+2)/2) * W/nf * 0.29'" 
ps="'2*int((nf+2)/2) * (W/nf + 0.29)'"
nrd="'0.29 / W'" nrs="'0.29 / W'"
sa=0 sb=0 sd=0
model=nfet_01v8
spiceprefix=X
}
C {/usr/local/share/pdk/sky130A/libs.tech/xschem/sky130_fd_pr/pfet_01v8.sym} 1420 380 0 0 {name=M46
W=0.44
L=0.15
nf=1
mult=1
ad="'int((nf+1)/2) * W/nf * 0.29'" 
pd="'2*int((nf+1)/2) * (W/nf + 0.29)'"
as="'int((nf+2)/2) * W/nf * 0.29'" 
ps="'2*int((nf+2)/2) * (W/nf + 0.29)'"
nrd="'0.29 / W'" nrs="'0.29 / W'"
sa=0 sb=0 sd=0
model=pfet_01v8
spiceprefix=X
}
C {/usr/local/share/pdk/sky130A/libs.tech/xschem/sky130_fd_pr/nfet_01v8.sym} 1420 490 0 0 {name=M47
W=0.58
L=0.15
nf=1 
mult=1
ad="'int((nf+1)/2) * W/nf * 0.29'" 
pd="'2*int((nf+1)/2) * (W/nf + 0.29)'"
as="'int((nf+2)/2) * W/nf * 0.29'" 
ps="'2*int((nf+2)/2) * (W/nf + 0.29)'"
nrd="'0.29 / W'" nrs="'0.29 / W'"
sa=0 sb=0 sd=0
model=nfet_01v8
spiceprefix=X
}
C {/usr/local/share/pdk/sky130A/libs.tech/xschem/sky130_fd_pr/nfet_01v8.sym} 1420 590 0 0 {name=M48
W=0.58
L=0.15
nf=1 
mult=1
ad="'int((nf+1)/2) * W/nf * 0.29'" 
pd="'2*int((nf+1)/2) * (W/nf + 0.29)'"
as="'int((nf+2)/2) * W/nf * 0.29'" 
ps="'2*int((nf+2)/2) * (W/nf + 0.29)'"
nrd="'0.29 / W'" nrs="'0.29 / W'"
sa=0 sb=0 sd=0
model=nfet_01v8
spiceprefix=X
}
C {/usr/local/share/pdk/sky130A/libs.tech/xschem/sky130_fd_pr/pfet_01v8.sym} 1620 380 0 0 {name=M49
W=0.88
L=0.15
nf=1
mult=1
ad="'int((nf+1)/2) * W/nf * 0.29'" 
pd="'2*int((nf+1)/2) * (W/nf + 0.29)'"
as="'int((nf+2)/2) * W/nf * 0.29'" 
ps="'2*int((nf+2)/2) * (W/nf + 0.29)'"
nrd="'0.29 / W'" nrs="'0.29 / W'"
sa=0 sb=0 sd=0
model=pfet_01v8
spiceprefix=X
}
C {/usr/local/share/pdk/sky130A/libs.tech/xschem/sky130_fd_pr/pfet_01v8.sym} 1620 490 0 0 {name=M50
W=0.88
L=0.15
nf=1
mult=1
ad="'int((nf+1)/2) * W/nf * 0.29'" 
pd="'2*int((nf+1)/2) * (W/nf + 0.29)'"
as="'int((nf+2)/2) * W/nf * 0.29'" 
ps="'2*int((nf+2)/2) * (W/nf + 0.29)'"
nrd="'0.29 / W'" nrs="'0.29 / W'"
sa=0 sb=0 sd=0
model=pfet_01v8
spiceprefix=X
}
C {/usr/local/share/pdk/sky130A/libs.tech/xschem/sky130_fd_pr/nfet_01v8.sym} 1620 590 0 0 {name=M51
W=0.38
L=0.15
nf=1 
mult=1
ad="'int((nf+1)/2) * W/nf * 0.29'" 
pd="'2*int((nf+1)/2) * (W/nf + 0.29)'"
as="'int((nf+2)/2) * W/nf * 0.29'" 
ps="'2*int((nf+2)/2) * (W/nf + 0.29)'"
nrd="'0.29 / W'" nrs="'0.29 / W'"
sa=0 sb=0 sd=0
model=nfet_01v8
spiceprefix=X
}
C {/usr/local/share/pdk/sky130A/libs.tech/xschem/sky130_fd_pr/pfet_01v8.sym} -190 -80 0 0 {name=M52
W=1
L=0.15
nf=1
mult=1
ad="'int((nf+1)/2) * W/nf * 0.29'" 
pd="'2*int((nf+1)/2) * (W/nf + 0.29)'"
as="'int((nf+2)/2) * W/nf * 0.29'" 
ps="'2*int((nf+2)/2) * (W/nf + 0.29)'"
nrd="'0.29 / W'" nrs="'0.29 / W'"
sa=0 sb=0 sd=0
model=pfet_01v8
spiceprefix=X
}
C {/usr/local/share/pdk/sky130A/libs.tech/xschem/sky130_fd_pr/nfet_01v8.sym} -190 10 0 0 {name=M53
W=1
L=0.15
nf=1 
mult=1
ad="'int((nf+1)/2) * W/nf * 0.29'" 
pd="'2*int((nf+1)/2) * (W/nf + 0.29)'"
as="'int((nf+2)/2) * W/nf * 0.29'" 
ps="'2*int((nf+2)/2) * (W/nf + 0.29)'"
nrd="'0.29 / W'" nrs="'0.29 / W'"
sa=0 sb=0 sd=0
model=nfet_01v8
spiceprefix=X
}
C {/usr/local/share/pdk/sky130A/libs.tech/xschem/sky130_fd_pr/pfet_01v8.sym} 360 840 1 0 {name=M54
W=1
L=0.15
nf=1
mult=1
ad="'int((nf+1)/2) * W/nf * 0.29'" 
pd="'2*int((nf+1)/2) * (W/nf + 0.29)'"
as="'int((nf+2)/2) * W/nf * 0.29'" 
ps="'2*int((nf+2)/2) * (W/nf + 0.29)'"
nrd="'0.29 / W'" nrs="'0.29 / W'"
sa=0 sb=0 sd=0
model=pfet_01v8
spiceprefix=X
}
C {/usr/local/share/pdk/sky130A/libs.tech/xschem/sky130_fd_pr/nfet_01v8.sym} 270 840 1 0 {name=M55
W=1
L=0.15
nf=1 
mult=1
ad="'int((nf+1)/2) * W/nf * 0.29'" 
pd="'2*int((nf+1)/2) * (W/nf + 0.29)'"
as="'int((nf+2)/2) * W/nf * 0.29'" 
ps="'2*int((nf+2)/2) * (W/nf + 0.29)'"
nrd="'0.29 / W'" nrs="'0.29 / W'"
sa=0 sb=0 sd=0
model=nfet_01v8
spiceprefix=X
}
C {/usr/local/share/pdk/sky130A/libs.tech/xschem/sky130_fd_pr/pfet_01v8.sym} 810 840 1 0 {name=M58
W=1
L=0.15
nf=1
mult=1
ad="'int((nf+1)/2) * W/nf * 0.29'" 
pd="'2*int((nf+1)/2) * (W/nf + 0.29)'"
as="'int((nf+2)/2) * W/nf * 0.29'" 
ps="'2*int((nf+2)/2) * (W/nf + 0.29)'"
nrd="'0.29 / W'" nrs="'0.29 / W'"
sa=0 sb=0 sd=0
model=pfet_01v8
spiceprefix=X
}
C {/usr/local/share/pdk/sky130A/libs.tech/xschem/sky130_fd_pr/nfet_01v8.sym} 720 840 1 0 {name=M59
W=1
L=0.15
nf=1 
mult=1
ad="'int((nf+1)/2) * W/nf * 0.29'" 
pd="'2*int((nf+1)/2) * (W/nf + 0.29)'"
as="'int((nf+2)/2) * W/nf * 0.29'" 
ps="'2*int((nf+2)/2) * (W/nf + 0.29)'"
nrd="'0.29 / W'" nrs="'0.29 / W'"
sa=0 sb=0 sd=0
model=nfet_01v8
spiceprefix=X
}
C {/usr/local/share/pdk/sky130A/libs.tech/xschem/sky130_fd_pr/pfet_01v8.sym} 1020 840 1 0 {name=M60
W=1
L=0.15
nf=1
mult=1
ad="'int((nf+1)/2) * W/nf * 0.29'" 
pd="'2*int((nf+1)/2) * (W/nf + 0.29)'"
as="'int((nf+2)/2) * W/nf * 0.29'" 
ps="'2*int((nf+2)/2) * (W/nf + 0.29)'"
nrd="'0.29 / W'" nrs="'0.29 / W'"
sa=0 sb=0 sd=0
model=pfet_01v8
spiceprefix=X
}
C {/usr/local/share/pdk/sky130A/libs.tech/xschem/sky130_fd_pr/nfet_01v8.sym} 930 840 1 0 {name=M61
W=1
L=0.15
nf=1 
mult=1
ad="'int((nf+1)/2) * W/nf * 0.29'" 
pd="'2*int((nf+1)/2) * (W/nf + 0.29)'"
as="'int((nf+2)/2) * W/nf * 0.29'" 
ps="'2*int((nf+2)/2) * (W/nf + 0.29)'"
nrd="'0.29 / W'" nrs="'0.29 / W'"
sa=0 sb=0 sd=0
model=nfet_01v8
spiceprefix=X
}
C {/usr/local/share/pdk/sky130A/libs.tech/xschem/sky130_fd_pr/pfet_01v8.sym} 1230 840 1 0 {name=M62
W=1
L=0.15
nf=1
mult=1
ad="'int((nf+1)/2) * W/nf * 0.29'" 
pd="'2*int((nf+1)/2) * (W/nf + 0.29)'"
as="'int((nf+2)/2) * W/nf * 0.29'" 
ps="'2*int((nf+2)/2) * (W/nf + 0.29)'"
nrd="'0.29 / W'" nrs="'0.29 / W'"
sa=0 sb=0 sd=0
model=pfet_01v8
spiceprefix=X
}
C {/usr/local/share/pdk/sky130A/libs.tech/xschem/sky130_fd_pr/nfet_01v8.sym} 1140 840 1 0 {name=M63
W=1
L=0.15
nf=1 
mult=1
ad="'int((nf+1)/2) * W/nf * 0.29'" 
pd="'2*int((nf+1)/2) * (W/nf + 0.29)'"
as="'int((nf+2)/2) * W/nf * 0.29'" 
ps="'2*int((nf+2)/2) * (W/nf + 0.29)'"
nrd="'0.29 / W'" nrs="'0.29 / W'"
sa=0 sb=0 sd=0
model=nfet_01v8
spiceprefix=X
}
C {/usr/local/share/pdk/sky130A/libs.tech/xschem/sky130_fd_pr/pfet_01v8.sym} 1430 840 1 0 {name=M64
W=1
L=0.15
nf=1
mult=1
ad="'int((nf+1)/2) * W/nf * 0.29'" 
pd="'2*int((nf+1)/2) * (W/nf + 0.29)'"
as="'int((nf+2)/2) * W/nf * 0.29'" 
ps="'2*int((nf+2)/2) * (W/nf + 0.29)'"
nrd="'0.29 / W'" nrs="'0.29 / W'"
sa=0 sb=0 sd=0
model=pfet_01v8
spiceprefix=X
}
C {/usr/local/share/pdk/sky130A/libs.tech/xschem/sky130_fd_pr/nfet_01v8.sym} 1340 840 1 0 {name=M65
W=1
L=0.15
nf=1 
mult=1
ad="'int((nf+1)/2) * W/nf * 0.29'" 
pd="'2*int((nf+1)/2) * (W/nf + 0.29)'"
as="'int((nf+2)/2) * W/nf * 0.29'" 
ps="'2*int((nf+2)/2) * (W/nf + 0.29)'"
nrd="'0.29 / W'" nrs="'0.29 / W'"
sa=0 sb=0 sd=0
model=nfet_01v8
spiceprefix=X
}
C {/usr/local/share/pdk/sky130A/libs.tech/xschem/sky130_fd_pr/pfet_01v8.sym} 1640 840 1 0 {name=M66
W=1
L=0.15
nf=1
mult=1
ad="'int((nf+1)/2) * W/nf * 0.29'" 
pd="'2*int((nf+1)/2) * (W/nf + 0.29)'"
as="'int((nf+2)/2) * W/nf * 0.29'" 
ps="'2*int((nf+2)/2) * (W/nf + 0.29)'"
nrd="'0.29 / W'" nrs="'0.29 / W'"
sa=0 sb=0 sd=0
model=pfet_01v8
spiceprefix=X
}
C {/usr/local/share/pdk/sky130A/libs.tech/xschem/sky130_fd_pr/nfet_01v8.sym} 1550 840 1 0 {name=M67
W=1
L=0.15
nf=1 
mult=1
ad="'int((nf+1)/2) * W/nf * 0.29'" 
pd="'2*int((nf+1)/2) * (W/nf + 0.29)'"
as="'int((nf+2)/2) * W/nf * 0.29'" 
ps="'2*int((nf+2)/2) * (W/nf + 0.29)'"
nrd="'0.29 / W'" nrs="'0.29 / W'"
sa=0 sb=0 sd=0
model=nfet_01v8
spiceprefix=X
}
C {/usr/local/share/pdk/sky130A/libs.tech/xschem/sky130_fd_pr/pfet_01v8.sym} -190 120 0 0 {name=M68
W=1
L=0.15
nf=1
mult=1
ad="'int((nf+1)/2) * W/nf * 0.29'" 
pd="'2*int((nf+1)/2) * (W/nf + 0.29)'"
as="'int((nf+2)/2) * W/nf * 0.29'" 
ps="'2*int((nf+2)/2) * (W/nf + 0.29)'"
nrd="'0.29 / W'" nrs="'0.29 / W'"
sa=0 sb=0 sd=0
model=pfet_01v8
spiceprefix=X
}
C {/usr/local/share/pdk/sky130A/libs.tech/xschem/sky130_fd_pr/nfet_01v8.sym} -190 210 0 0 {name=M69
W=1
L=0.15
nf=1 
mult=1
ad="'int((nf+1)/2) * W/nf * 0.29'" 
pd="'2*int((nf+1)/2) * (W/nf + 0.29)'"
as="'int((nf+2)/2) * W/nf * 0.29'" 
ps="'2*int((nf+2)/2) * (W/nf + 0.29)'"
nrd="'0.29 / W'" nrs="'0.29 / W'"
sa=0 sb=0 sd=0
model=nfet_01v8
spiceprefix=X
}
C {/usr/local/share/pdk/sky130A/libs.tech/xschem/sky130_fd_pr/pfet_01v8.sym} -190 330 0 0 {name=M70
W=1
L=0.15
nf=1
mult=1
ad="'int((nf+1)/2) * W/nf * 0.29'" 
pd="'2*int((nf+1)/2) * (W/nf + 0.29)'"
as="'int((nf+2)/2) * W/nf * 0.29'" 
ps="'2*int((nf+2)/2) * (W/nf + 0.29)'"
nrd="'0.29 / W'" nrs="'0.29 / W'"
sa=0 sb=0 sd=0
model=pfet_01v8
spiceprefix=X
}
C {/usr/local/share/pdk/sky130A/libs.tech/xschem/sky130_fd_pr/nfet_01v8.sym} -190 420 0 0 {name=M71
W=1
L=0.15
nf=1 
mult=1
ad="'int((nf+1)/2) * W/nf * 0.29'" 
pd="'2*int((nf+1)/2) * (W/nf + 0.29)'"
as="'int((nf+2)/2) * W/nf * 0.29'" 
ps="'2*int((nf+2)/2) * (W/nf + 0.29)'"
nrd="'0.29 / W'" nrs="'0.29 / W'"
sa=0 sb=0 sd=0
model=nfet_01v8
spiceprefix=X
}
C {/usr/local/share/pdk/sky130A/libs.tech/xschem/sky130_fd_pr/pfet_01v8.sym} -410 330 0 0 {name=M72
W=1
L=0.15
nf=1
mult=1
ad="'int((nf+1)/2) * W/nf * 0.29'" 
pd="'2*int((nf+1)/2) * (W/nf + 0.29)'"
as="'int((nf+2)/2) * W/nf * 0.29'" 
ps="'2*int((nf+2)/2) * (W/nf + 0.29)'"
nrd="'0.29 / W'" nrs="'0.29 / W'"
sa=0 sb=0 sd=0
model=pfet_01v8
spiceprefix=X
}
C {/usr/local/share/pdk/sky130A/libs.tech/xschem/sky130_fd_pr/nfet_01v8.sym} -410 420 0 0 {name=M73
W=1
L=0.15
nf=1 
mult=1
ad="'int((nf+1)/2) * W/nf * 0.29'" 
pd="'2*int((nf+1)/2) * (W/nf + 0.29)'"
as="'int((nf+2)/2) * W/nf * 0.29'" 
ps="'2*int((nf+2)/2) * (W/nf + 0.29)'"
nrd="'0.29 / W'" nrs="'0.29 / W'"
sa=0 sb=0 sd=0
model=nfet_01v8
spiceprefix=X
}
C {/usr/local/share/pdk/sky130A/libs.tech/xschem/sky130_fd_pr/nfet_01v8.sym} 200 810 3 0 {name=M74
W=1
L=0.15
nf=1 
mult=1
ad="'int((nf+1)/2) * W/nf * 0.29'" 
pd="'2*int((nf+1)/2) * (W/nf + 0.29)'"
as="'int((nf+2)/2) * W/nf * 0.29'" 
ps="'2*int((nf+2)/2) * (W/nf + 0.29)'"
nrd="'0.29 / W'" nrs="'0.29 / W'"
sa=0 sb=0 sd=0
model=nfet_01v8
spiceprefix=X
}
C {/usr/local/share/pdk/sky130A/libs.tech/xschem/sky130_fd_pr/nfet_01v8.sym} 670 810 3 0 {name=M75
W=1
L=0.15
nf=1 
mult=1
ad="'int((nf+1)/2) * W/nf * 0.29'" 
pd="'2*int((nf+1)/2) * (W/nf + 0.29)'"
as="'int((nf+2)/2) * W/nf * 0.29'" 
ps="'2*int((nf+2)/2) * (W/nf + 0.29)'"
nrd="'0.29 / W'" nrs="'0.29 / W'"
sa=0 sb=0 sd=0
model=nfet_01v8
spiceprefix=X
}
C {/usr/local/share/pdk/sky130A/libs.tech/xschem/sky130_fd_pr/nfet_01v8.sym} 1080 810 3 0 {name=M76
W=1
L=0.15
nf=1 
mult=1
ad="'int((nf+1)/2) * W/nf * 0.29'" 
pd="'2*int((nf+1)/2) * (W/nf + 0.29)'"
as="'int((nf+2)/2) * W/nf * 0.29'" 
ps="'2*int((nf+2)/2) * (W/nf + 0.29)'"
nrd="'0.29 / W'" nrs="'0.29 / W'"
sa=0 sb=0 sd=0
model=nfet_01v8
spiceprefix=X
}
C {/usr/local/share/pdk/sky130A/libs.tech/xschem/sky130_fd_pr/nfet_01v8.sym} 1490 810 3 0 {name=M77
W=1
L=0.15
nf=1 
mult=1
ad="'int((nf+1)/2) * W/nf * 0.29'" 
pd="'2*int((nf+1)/2) * (W/nf + 0.29)'"
as="'int((nf+2)/2) * W/nf * 0.29'" 
ps="'2*int((nf+2)/2) * (W/nf + 0.29)'"
nrd="'0.29 / W'" nrs="'0.29 / W'"
sa=0 sb=0 sd=0
model=nfet_01v8
spiceprefix=X
}
C {/usr/local/share/pdk/sky130A/libs.tech/xschem/sky130_fd_pr/pfet_01v8.sym} 440 810 3 0 {name=M78
W=1
L=0.15
nf=1
mult=1
ad="'int((nf+1)/2) * W/nf * 0.29'" 
pd="'2*int((nf+1)/2) * (W/nf + 0.29)'"
as="'int((nf+2)/2) * W/nf * 0.29'" 
ps="'2*int((nf+2)/2) * (W/nf + 0.29)'"
nrd="'0.29 / W'" nrs="'0.29 / W'"
sa=0 sb=0 sd=0
model=pfet_01v8
spiceprefix=X
}
C {/usr/local/share/pdk/sky130A/libs.tech/xschem/sky130_fd_pr/pfet_01v8.sym} 870 810 3 0 {name=M79
W=1
L=0.15
nf=1
mult=1
ad="'int((nf+1)/2) * W/nf * 0.29'" 
pd="'2*int((nf+1)/2) * (W/nf + 0.29)'"
as="'int((nf+2)/2) * W/nf * 0.29'" 
ps="'2*int((nf+2)/2) * (W/nf + 0.29)'"
nrd="'0.29 / W'" nrs="'0.29 / W'"
sa=0 sb=0 sd=0
model=pfet_01v8
spiceprefix=X
}
C {/usr/local/share/pdk/sky130A/libs.tech/xschem/sky130_fd_pr/pfet_01v8.sym} 1290 810 3 0 {name=M80
W=1
L=0.15
nf=1
mult=1
ad="'int((nf+1)/2) * W/nf * 0.29'" 
pd="'2*int((nf+1)/2) * (W/nf + 0.29)'"
as="'int((nf+2)/2) * W/nf * 0.29'" 
ps="'2*int((nf+2)/2) * (W/nf + 0.29)'"
nrd="'0.29 / W'" nrs="'0.29 / W'"
sa=0 sb=0 sd=0
model=pfet_01v8
spiceprefix=X
}
C {/usr/local/share/pdk/sky130A/libs.tech/xschem/sky130_fd_pr/pfet_01v8.sym} -490 -70 0 0 {name=M81
W=1
L=0.15
nf=1
mult=1
ad="'int((nf+1)/2) * W/nf * 0.29'" 
pd="'2*int((nf+1)/2) * (W/nf + 0.29)'"
as="'int((nf+2)/2) * W/nf * 0.29'" 
ps="'2*int((nf+2)/2) * (W/nf + 0.29)'"
nrd="'0.29 / W'" nrs="'0.29 / W'"
sa=0 sb=0 sd=0
model=pfet_01v8
spiceprefix=X
}
C {/usr/local/share/pdk/sky130A/libs.tech/xschem/sky130_fd_pr/nfet_01v8.sym} -450 70 2 0 {name=M82
W=1
L=0.15
nf=1 
mult=1
ad="'int((nf+1)/2) * W/nf * 0.29'" 
pd="'2*int((nf+1)/2) * (W/nf + 0.29)'"
as="'int((nf+2)/2) * W/nf * 0.29'" 
ps="'2*int((nf+2)/2) * (W/nf + 0.29)'"
nrd="'0.29 / W'" nrs="'0.29 / W'"
sa=0 sb=0 sd=0
model=nfet_01v8
spiceprefix=X
}
C {/usr/local/share/pdk/sky130A/libs.tech/xschem/sky130_fd_pr/nfet_01v8.sym} -490 210 0 0 {name=M83
W=1
L=0.15
nf=1 
mult=1
ad="'int((nf+1)/2) * W/nf * 0.29'" 
pd="'2*int((nf+1)/2) * (W/nf + 0.29)'"
as="'int((nf+2)/2) * W/nf * 0.29'" 
ps="'2*int((nf+2)/2) * (W/nf + 0.29)'"
nrd="'0.29 / W'" nrs="'0.29 / W'"
sa=0 sb=0 sd=0
model=nfet_01v8
spiceprefix=X
}
C {/usr/local/share/pdk/sky130A/libs.tech/xschem/sky130_fd_pr/pfet_01v8.sym} -760 100 0 0 {name=M84
W=1
L=0.15
nf=1
mult=1
ad="'int((nf+1)/2) * W/nf * 0.29'" 
pd="'2*int((nf+1)/2) * (W/nf + 0.29)'"
as="'int((nf+2)/2) * W/nf * 0.29'" 
ps="'2*int((nf+2)/2) * (W/nf + 0.29)'"
nrd="'0.29 / W'" nrs="'0.29 / W'"
sa=0 sb=0 sd=0
model=pfet_01v8
spiceprefix=X
}
C {/usr/local/share/pdk/sky130A/libs.tech/xschem/sky130_fd_pr/nfet_01v8.sym} -760 190 0 0 {name=M85
W=1
L=0.15
nf=1 
mult=1
ad="'int((nf+1)/2) * W/nf * 0.29'" 
pd="'2*int((nf+1)/2) * (W/nf + 0.29)'"
as="'int((nf+2)/2) * W/nf * 0.29'" 
ps="'2*int((nf+2)/2) * (W/nf + 0.29)'"
nrd="'0.29 / W'" nrs="'0.29 / W'"
sa=0 sb=0 sd=0
model=nfet_01v8
spiceprefix=X
}
C {gnd.sym} 220 70 0 0 {name=l1 lab=GND}
C {gnd.sym} 620 70 0 0 {name=l2 lab=GND}
C {gnd.sym} -740 230 0 0 {name=l3 lab=GND}
C {gnd.sym} 1020 70 0 0 {name=l4 lab=GND}
C {gnd.sym} 1420 70 0 0 {name=l5 lab=GND}
C {gnd.sym} 80 240 0 0 {name=l6 lab=GND}
C {vdd.sym} -740 60 0 0 {name=l7 lab=VDD}
C {vdd.sym} 420 70 0 0 {name=l8 lab=VDD}
C {vdd.sym} 820 70 0 0 {name=l9 lab=VDD}
C {vdd.sym} 1220 70 0 0 {name=l10 lab=VDD}
C {vdd.sym} 1620 70 0 0 {name=l11 lab=VDD}
C {vdd.sym} 80 -120 0 0 {name=l12 lab=VDD}
C {vdd.sym} 240 300 0 0 {name=l13 lab=VDD}
C {gnd.sym} 240 660 0 0 {name=l14 lab=GND}
C {gnd.sym} 140 790 0 0 {name=l15 lab=GND}
C {gnd.sym} 620 790 0 0 {name=l16 lab=GND}
C {gnd.sym} 1030 790 0 0 {name=l17 lab=GND}
C {gnd.sym} 1440 790 0 0 {name=l18 lab=GND}
C {vdd.sym} 390 790 0 0 {name=l19 lab=VDD}
C {vdd.sym} 820 790 0 0 {name=l20 lab=VDD}
C {vdd.sym} 1240 790 0 0 {name=l21 lab=VDD}
C {vdd.sym} 400 860 0 0 {name=l22 lab=VDD}
C {vdd.sym} 630 860 0 0 {name=l23 lab=VDD}
C {vdd.sym} 850 860 0 0 {name=l24 lab=VDD}
C {vdd.sym} 1060 860 0 0 {name=l25 lab=VDD}
C {vdd.sym} 1270 860 0 0 {name=l26 lab=VDD}
C {vdd.sym} 1470 860 0 0 {name=l27 lab=VDD}
C {vdd.sym} 1680 860 0 0 {name=l28 lab=VDD}
C {gnd.sym} 220 860 0 0 {name=l29 lab=GND}
C {gnd.sym} 450 860 0 0 {name=l30 lab=GND}
C {gnd.sym} 680 860 0 0 {name=l31 lab=GND}
C {gnd.sym} 890 860 0 0 {name=l32 lab=GND}
C {gnd.sym} 1100 860 0 0 {name=l33 lab=GND}
C {gnd.sym} 1510 860 0 0 {name=l34 lab=GND}
C {gnd.sym} 1300 860 0 0 {name=l35 lab=GND}
C {lab_pin.sym} 310 980 0 0 {name=p1 sig_type=std_logic lab=t0}
C {lab_pin.sym} 540 980 0 0 {name=p2 sig_type=std_logic lab=t1
}
C {lab_pin.sym} 770 980 0 0 {name=p3 sig_type=std_logic lab=t2}
C {lab_pin.sym} 970 980 0 0 {name=p4 sig_type=std_logic lab=t3}
C {lab_pin.sym} 1180 980 0 0 {name=p5 sig_type=std_logic lab=t4}
C {lab_pin.sym} 1390 980 0 0 {name=p6 sig_type=std_logic lab=t5}
C {lab_pin.sym} 1590 980 0 0 {name=p7 sig_type=std_logic lab=t6}
C {gnd.sym} -470 270 0 0 {name=l36 lab=GND}
C {gnd.sym} -520 110 0 0 {name=l37 lab=GND}
C {vdd.sym} -170 -120 0 0 {name=l38 lab=VDD}
C {vdd.sym} -470 -130 0 0 {name=l39 lab=VDD}
C {gnd.sym} -170 50 0 0 {name=l40 lab=GND}
C {gnd.sym} -170 250 0 0 {name=l41 lab=GND}
C {gnd.sym} -170 460 0 0 {name=l42 lab=GND}
C {vdd.sym} -130 80 0 0 {name=l43 lab=VDD}
C {vdd.sym} -130 290 0 0 {name=l44 lab=VDD}
C {vdd.sym} -390 290 0 0 {name=l45 lab=VDD}
C {gnd.sym} -390 460 0 0 {name=l46 lab=GND}
C {lab_pin.sym} -870 -20 0 0 {name=p8 sig_type=std_logic lab=clkA}
C {lab_pin.sym} -870 140 0 0 {name=p9 sig_type=std_logic lab=clkB}
C {vsource.sym} -900 390 0 0 {name=V1 value="pulse(0 1.8 0 100p 100p 4n 8n)" savecurrent=false}
C {vsource.sym} -720 530 0 0 {name=V2 value=1.8 savecurrent=false}
C {vsource.sym} -1100 960 0 0 {name=V3 value="pulse(0 1.8 0 100p 100p 3n 6n)" savecurrent=false}
C {lab_pin.sym} -900 340 0 0 {name=p10 sig_type=std_logic lab=clkA}
C {lab_pin.sym} -1000 840 1 0 {name=p11 sig_type=std_logic lab=clkB}
C {vdd.sym} -720 480 0 0 {name=l47 lab=VDD}
C {gnd.sym} -720 580 0 0 {name=l48 lab=GND}
C {gnd.sym} -900 440 0 0 {name=l49 lab=GND}
C {gnd.sym} -1100 1010 0 0 {name=l50 lab=GND}
C {code_shown.sym} -530 550 0 0 {name=VRO2 only_toplevel=false value=".lib /usr/local/share/pdk/sky130A/libs.tech/ngspice/sky130.lib.spice tt
.tran 10p 100n
.save all
.end"}
C {/usr/local/share/pdk/sky130A/libs.tech/xschem/sky130_fd_pr/pfet_01v8.sym} 580 840 1 0 {name=M56
W=1
L=0.15
nf=1
mult=1
ad="'int((nf+1)/2) * W/nf * 0.29'" 
pd="'2*int((nf+1)/2) * (W/nf + 0.29)'"
as="'int((nf+2)/2) * W/nf * 0.29'" 
ps="'2*int((nf+2)/2) * (W/nf + 0.29)'"
nrd="'0.29 / W'" nrs="'0.29 / W'"
sa=0 sb=0 sd=0
model=pfet_01v8
spiceprefix=X
}
C {/usr/local/share/pdk/sky130A/libs.tech/xschem/sky130_fd_pr/nfet_01v8.sym} 500 840 1 0 {name=M57
W=1
L=0.15
nf=1 
mult=1
ad="'int((nf+1)/2) * W/nf * 0.29'" 
pd="'2*int((nf+1)/2) * (W/nf + 0.29)'"
as="'int((nf+2)/2) * W/nf * 0.29'" 
ps="'2*int((nf+2)/2) * (W/nf + 0.29)'"
nrd="'0.29 / W'" nrs="'0.29 / W'"
sa=0 sb=0 sd=0
model=nfet_01v8
spiceprefix=X
}
C {lab_pin.sym} -60 -40 0 0 {name=p12 sig_type=std_logic lab=stop}
C {lab_pin.sym} 0 380 1 0 {name=p13 sig_type=std_logic lab=start}
C {/usr/local/share/pdk/sky130A/libs.tech/xschem/sky130_fd_pr/pfet_01v8.sym} -880 790 0 0 {name=M86
W=1
L=0.15
nf=1
mult=1
ad="'int((nf+1)/2) * W/nf * 0.29'" 
pd="'2*int((nf+1)/2) * (W/nf + 0.29)'"
as="'int((nf+2)/2) * W/nf * 0.29'" 
ps="'2*int((nf+2)/2) * (W/nf + 0.29)'"
nrd="'0.29 / W'" nrs="'0.29 / W'"
sa=0 sb=0 sd=0
model=pfet_01v8
spiceprefix=X
}
C {/usr/local/share/pdk/sky130A/libs.tech/xschem/sky130_fd_pr/nfet_01v8.sym} -880 880 0 0 {name=M87
W=1
L=0.15
nf=1 
mult=1
ad="'int((nf+1)/2) * W/nf * 0.29'" 
pd="'2*int((nf+1)/2) * (W/nf + 0.29)'"
as="'int((nf+2)/2) * W/nf * 0.29'" 
ps="'2*int((nf+2)/2) * (W/nf + 0.29)'"
nrd="'0.29 / W'" nrs="'0.29 / W'"
sa=0 sb=0 sd=0
model=nfet_01v8
spiceprefix=X
}
C {vdd.sym} -860 750 0 0 {name=l51 lab=VDD}
C {gnd.sym} -860 920 0 0 {name=l52 lab=GND}
